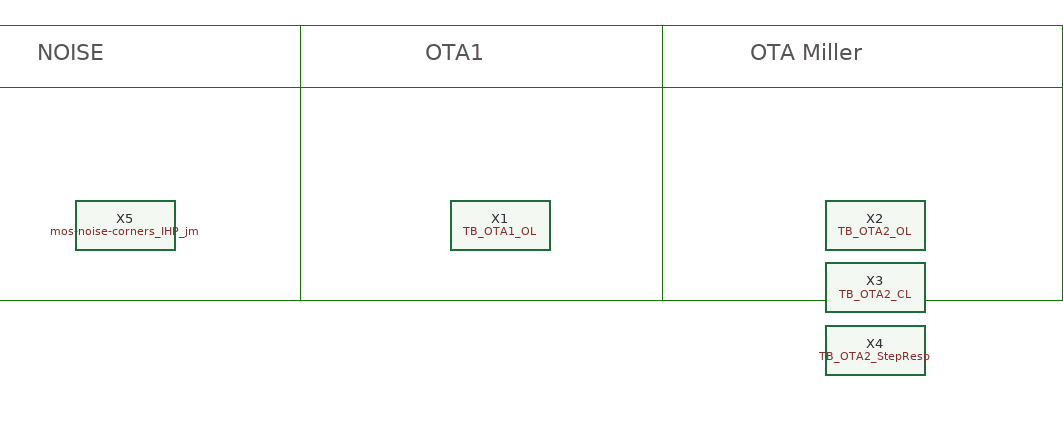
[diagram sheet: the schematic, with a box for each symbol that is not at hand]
v {xschem version=3.4.6 file_version=1.2}
G {}
K {}
V {}
S {}
E {}
L 4 -4290 -400 -4290 -190 {}
L 4 -4000 -400 -4000 -180 {}
L 4 -3680 -400 -3680 -180 {}
L 4 -4290 -400 -3680 -400 {}
L 4 -4290 -180 -3680 -180 {}
L 4 -4290 -190 -4290 -180 {}
L 4 -4290 -350 -3680 -350 {}
L 4 -4580 -350 -4290 -350 {}
L 4 -4580 -400 -4580 -350 {}
L 4 -4580 -400 -4290 -400 {}
L 4 -4580 -350 -4580 -180 {}
L 4 -4580 -180 -4290 -180 {}
T {OTA1} -4190 -390 0 0 0.6 0.6 {}
T {OTA Miller} -3930 -390 0 0 0.6 0.6 {}
T {NOISE} -4500 -390 0 0 0.6 0.6 {}
C {title.sym} -4270 -70 0 0 {name=l1 author="Prof. Jorge Marin - EIE-PUCV - 2026-02"}
C {../Tarea_2/TB_OTA1_OL.sym} -4130 -240 0 0 {name=X1}
C {../Tarea_2/TB_OTA2_OL.sym} -3830 -240 0 0 {name=X2}
C {../Tarea_2/TB_OTA2_CL.sym} -3830 -190 0 0 {name=X3}
C {../Tarea_2/TB_OTA2_StepResp.sym} -3830 -140 0 0 {name=X4}
C {../Tarea_2/mos-noise-corners_IHP_jm.sym} -4430 -240 0 0 {name=X5}
